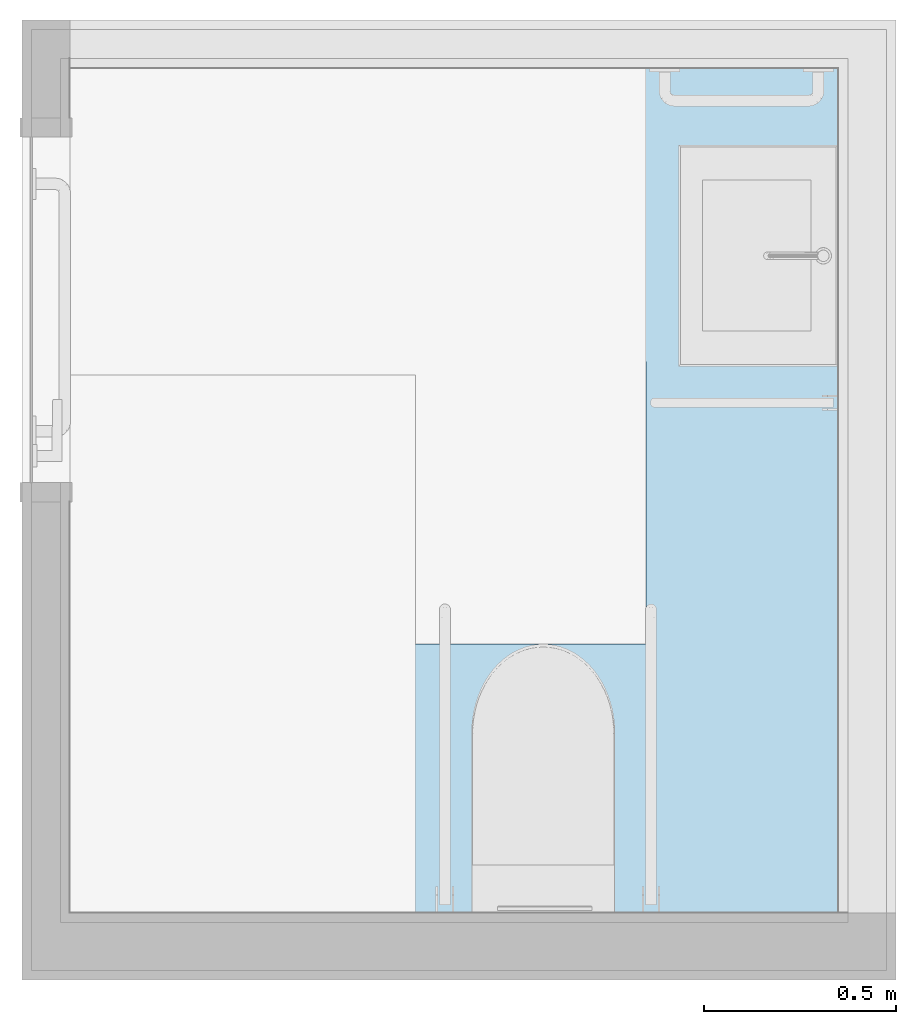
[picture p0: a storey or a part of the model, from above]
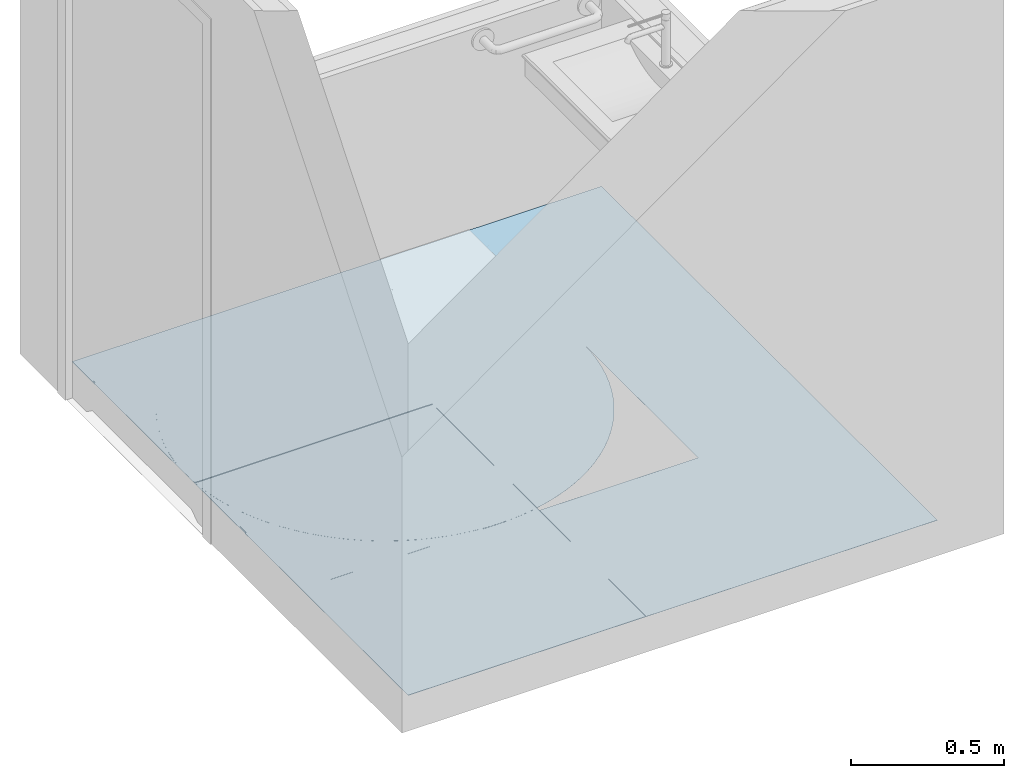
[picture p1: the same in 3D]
Properties of the parts of a building model (IFC2X3)

# File
Description: ViewDefinition [CoordinationView_V2.0]
File name: kolizja nr 9 - 2018.ifc
Time: 2025-11-21T15:24:08
Written by: IFC-manager for SketchUp (5.5.4)
Made in: SketchUp 2026 (26.0.429)

# IfcSite, Default Site
RefElevation: 0 mm

# IfcBuilding, Default Building
ElevationOfRefHeight: 0 mm; ElevationOfTerrain: 0 mm

# IfcBuildingStorey, Default Building Storey
In: Default Building
Elevation: 0 mm
Parametry kolizji SG - Elementkolizyjnykonstrukcyjnyinstalacyjny: Wariant 1; ElementsystemuSaintGobain: Łazienki – przestrzeń dla OZN; Izolacyjnoscakustyczna: -; Klasaodpornosciogniowej: -; LODlevelofDevelopment: 400; Nrdetalu: 5.00.01; Opis: Rysunek przestrzeni manewrowych niezbędnych do umożliwienia użytkowania przestrzeni przez osobę z niepełnosprawnością; Producent: SAINT-GOBAIN; Sposobwykonania: W przypadku wystÄ…pienia kolizji przestrzeni manewrowej z przegroda wydzielajÄ…cÄ… pomieszczenie lub z wyposaÅ¼eniem pomieszczenia naleÅ¼y rozwaÅ¼yÄ‡ zmianÄ™ ukÅ‚adu bÄ…dÅº paramentÃ³w pomieszczenia. NaleÅ¼y zachowaÄ‡ przestrzeÅ„ manewrowÄ… o wymiarze 150x150cm, nie wchodzÄ…cÄ… w kolizje z elementami staÅ‚ymi wyposaÅ¼enia. NaleÅ¼y zachowaÄ‡ przestrzeÅ„ 90x140 cm pomiÄ™dzy krawÄ™dziÄ… miski ustÄ™powej, a Å›cianÄ… wydzielajÄ…cÄ… pomieszczenie. Przestrzenie te mogÄ… wchodziÄ‡ w kolizjÄ™ z uchylnymi elementemi wyposaÅ¼enia. Miminalna szerokoÅ›Ä‡ drzwi w Å›wietle wynosi 90 cm.; Typkolizji: miękka; Warianty: Łazienka na planie kwadratu

# IfcDoor (3)
In: Default Building Storey
Name | Material
Ościeżnica | Metal_06_1K
Klamka | M05_Graphite_Haze
Drzwi | Metal_06_1K

# IfcFlowTerminal: Toaleta
In: Default Building Storey
Type - PredefinedType: BATH
Material: Color_000

# IfcFlowTerminal: Umywalka
In: Default Building Storey
Type - PredefinedType: BATH
Material: RPS_Lamp_white

# IfcFurnishingElement: Bateria
In: Default Building Storey
Material: M05_Graphite_Haze

# IfcFurnishingElement: Poręcz stała dla osób z niepełnosprawnością
In: Default Building Storey
Material: M05_Graphite_Haze

# IfcFurnishingElement: Poręcz stała na drzwi dla osób z niepełnosprawnością
In: Default Building Storey
Material: M05_Graphite_Haze

# IfcFurnishingElement: Poręcz uchylna dla osób z niepełnosprawnością (3)
In: Default Building Storey
Material: M05_Graphite_Haze

# IfcSlab: Grupuj#11, Podłoga
In: Default Building Storey
Type - PredefinedType: FLOOR
Material: Marble_01_1K

# IfcSlab: Podłoga
In: Default Building Storey
Type - PredefinedType: FLOOR
Material: Marble_01_1K

# IfcSlab: Przestrzeń manewrowa 150x150 cm
In: Default Building Storey
Type - PredefinedType: FLOOR
Material: A05_Cherry_Blaze1

# IfcSlab: Przestrzeń manewrowa liczona od krawędzi miski ustępowej nie może być mniejsza niż 90x140 cm
In: Default Building Storey
Type - PredefinedType: FLOOR
Material: J05_Violet_Prism1

# IfcWall: Grupuj#1, Ściany
In: Default Building Storey
Material: Plaster_02_1K

# IfcWall: Grupuj#7, Ściany
In: Default Building Storey
Material: M02_Ash_Whisper

# IfcWall: Grupuj#8, Płytki
In: Default Building Storey
Material: Marble_01_1K

# IfcWall: Grupuj#9, Ściany
In: Default Building Storey
Material: Undefined7

# IfcWall: Ściany
In: Default Building Storey
Material: J05_Violet_Prism1
